VERSION 5.7 ;
  NOWIREEXTENSIONATPIN ON ;
  DIVIDERCHAR "/" ;
  BUSBITCHARS "[]" ;
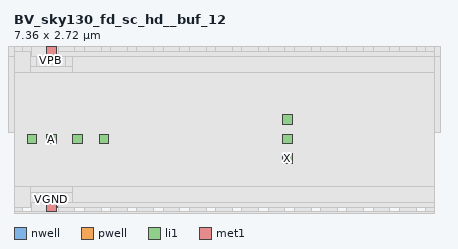
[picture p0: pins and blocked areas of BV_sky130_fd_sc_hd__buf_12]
MACRO BV_sky130_fd_sc_hd__buf_12
  CLASS BLOCK ;
  FOREIGN BV_sky130_fd_sc_hd__buf_12 ;
  ORIGIN 0.000 0.000 ;
  SIZE 7.360 BY 2.720 ;
  PIN VPB
    PORT
      LAYER nwell ;
        RECT 0.570 2.635 0.740 2.805 ;
    END
  END VPB
  PIN VNB
    PORT
      LAYER pwell ;
        RECT 0.570 -0.085 0.740 0.085 ;
    END
  END VNB
  PIN VGND
    USE GROUND ;
    PORT
      LAYER li1 ;
        RECT 0.570 -0.085 0.740 0.085 ;
    END
    PORT
      LAYER met1 ;
        RECT 0.570 -0.085 0.740 0.085 ;
    END
  END VGND
  PIN VPWR
    USE POWER ;
    PORT
      LAYER li1 ;
        RECT 0.570 2.635 0.740 2.805 ;
    END
    PORT
      LAYER met1 ;
        RECT 0.570 2.635 0.740 2.805 ;
    END
  END VPWR
  PIN A
    PORT
      LAYER li1 ;
        RECT 1.490 1.105 1.660 1.275 ;
    END
    PORT
      LAYER li1 ;
        RECT 1.030 1.105 1.200 1.275 ;
    END
    PORT
      LAYER li1 ;
        RECT 0.570 1.105 0.740 1.275 ;
    END
    PORT
      LAYER li1 ;
        RECT 0.230 1.105 0.400 1.275 ;
    END
  END A
  PIN X
    PORT
      LAYER li1 ;
        RECT 4.710 0.765 4.880 0.935 ;
    END
    PORT
      LAYER li1 ;
        RECT 4.710 1.105 4.880 1.275 ;
    END
    PORT
      LAYER li1 ;
        RECT 4.710 1.445 4.880 1.615 ;
    END
  END X
  OBS
      LAYER nwell ;
        RECT -0.190 2.805 7.550 2.910 ;
        RECT -0.190 2.635 0.570 2.805 ;
        RECT 0.740 2.635 7.550 2.805 ;
        RECT -0.190 1.305 7.550 2.635 ;
        RECT 0.000 0.085 7.360 1.305 ;
      LAYER li1 ;
        RECT 0.000 2.720 0.145 2.805 ;
        RECT 0.315 2.720 0.570 2.805 ;
        RECT 0.000 2.635 0.570 2.720 ;
        RECT 0.775 2.720 1.065 2.805 ;
        RECT 1.235 2.720 1.525 2.805 ;
        RECT 1.695 2.720 1.985 2.805 ;
        RECT 2.155 2.720 2.445 2.805 ;
        RECT 2.615 2.720 2.905 2.805 ;
        RECT 3.075 2.720 3.365 2.805 ;
        RECT 3.535 2.720 3.825 2.805 ;
        RECT 3.995 2.720 4.285 2.805 ;
        RECT 4.455 2.720 4.745 2.805 ;
        RECT 4.915 2.720 5.205 2.805 ;
        RECT 5.375 2.720 5.665 2.805 ;
        RECT 5.835 2.720 6.125 2.805 ;
        RECT 6.295 2.720 6.585 2.805 ;
        RECT 6.755 2.720 7.045 2.805 ;
        RECT 7.215 2.720 7.360 2.805 ;
        RECT 0.775 2.635 7.360 2.720 ;
        RECT 0.000 2.465 0.400 2.635 ;
        RECT 0.910 2.465 7.360 2.635 ;
        RECT 0.000 1.785 7.360 2.465 ;
        RECT 0.000 1.445 4.540 1.785 ;
        RECT 0.000 0.935 0.060 1.445 ;
        RECT 1.830 0.935 4.540 1.445 ;
        RECT 0.000 0.595 4.540 0.935 ;
        RECT 5.050 0.595 7.360 1.785 ;
        RECT 0.000 0.255 7.360 0.595 ;
        RECT 0.000 0.085 0.400 0.255 ;
        RECT 0.910 0.085 7.360 0.255 ;
        RECT 0.000 0.000 0.570 0.085 ;
        RECT 0.000 -0.085 0.145 0.000 ;
        RECT 0.315 -0.085 0.570 0.000 ;
        RECT 0.775 0.000 7.360 0.085 ;
        RECT 0.775 -0.085 1.065 0.000 ;
        RECT 1.235 -0.085 1.525 0.000 ;
        RECT 1.695 -0.085 1.985 0.000 ;
        RECT 2.155 -0.085 2.445 0.000 ;
        RECT 2.615 -0.085 2.905 0.000 ;
        RECT 3.075 -0.085 3.365 0.000 ;
        RECT 3.535 -0.085 3.825 0.000 ;
        RECT 3.995 -0.085 4.285 0.000 ;
        RECT 4.455 -0.085 4.745 0.000 ;
        RECT 4.915 -0.085 5.205 0.000 ;
        RECT 5.375 -0.085 5.665 0.000 ;
        RECT 5.835 -0.085 6.125 0.000 ;
        RECT 6.295 -0.085 6.585 0.000 ;
        RECT 6.755 -0.085 7.045 0.000 ;
        RECT 7.215 -0.085 7.360 0.000 ;
      LAYER met1 ;
        RECT 0.000 2.805 7.360 2.960 ;
        RECT 0.000 2.720 0.145 2.805 ;
        RECT 0.000 2.355 0.290 2.720 ;
        RECT 0.315 2.635 0.570 2.805 ;
        RECT 0.775 2.720 1.065 2.805 ;
        RECT 1.235 2.720 1.525 2.805 ;
        RECT 1.695 2.720 1.985 2.805 ;
        RECT 2.155 2.720 2.445 2.805 ;
        RECT 2.615 2.720 2.905 2.805 ;
        RECT 3.075 2.720 3.365 2.805 ;
        RECT 3.535 2.720 3.825 2.805 ;
        RECT 3.995 2.720 4.285 2.805 ;
        RECT 4.455 2.720 4.745 2.805 ;
        RECT 4.915 2.720 5.205 2.805 ;
        RECT 5.375 2.720 5.665 2.805 ;
        RECT 5.835 2.720 6.125 2.805 ;
        RECT 6.295 2.720 6.585 2.805 ;
        RECT 6.755 2.720 7.045 2.805 ;
        RECT 7.215 2.720 7.360 2.805 ;
        RECT 0.775 2.635 7.360 2.720 ;
        RECT 1.020 2.355 7.360 2.635 ;
        RECT 0.000 0.365 7.360 2.355 ;
        RECT 0.000 0.000 0.290 0.365 ;
        RECT 1.020 0.085 7.360 0.365 ;
        RECT 0.000 -0.085 0.145 0.000 ;
        RECT 0.315 -0.085 0.570 0.085 ;
        RECT 0.775 0.000 7.360 0.085 ;
        RECT 0.775 -0.085 1.065 0.000 ;
        RECT 1.235 -0.085 1.525 0.000 ;
        RECT 1.695 -0.085 1.985 0.000 ;
        RECT 2.155 -0.085 2.445 0.000 ;
        RECT 2.615 -0.085 2.905 0.000 ;
        RECT 3.075 -0.085 3.365 0.000 ;
        RECT 3.535 -0.085 3.825 0.000 ;
        RECT 3.995 -0.085 4.285 0.000 ;
        RECT 4.455 -0.085 4.745 0.000 ;
        RECT 4.915 -0.085 5.205 0.000 ;
        RECT 5.375 -0.085 5.665 0.000 ;
        RECT 5.835 -0.085 6.125 0.000 ;
        RECT 6.295 -0.085 6.585 0.000 ;
        RECT 6.755 -0.085 7.045 0.000 ;
        RECT 7.215 -0.085 7.360 0.000 ;
        RECT 0.000 -0.240 7.360 -0.085 ;
  END
END BV_sky130_fd_sc_hd__buf_12
END LIBRARY

